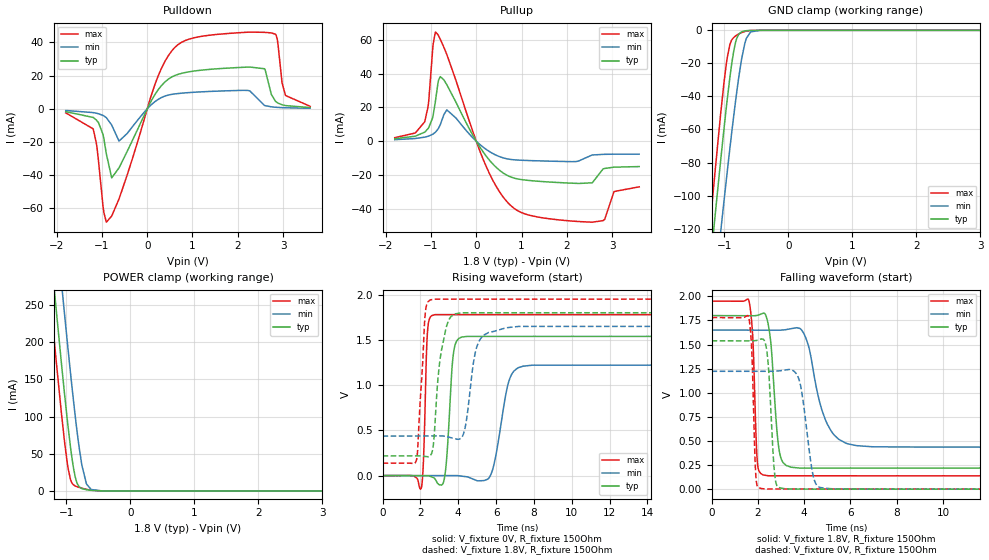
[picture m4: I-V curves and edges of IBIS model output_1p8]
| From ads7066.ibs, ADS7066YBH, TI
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|   output_1p8 Model
[Model]   output_1p8
Model_type   3-state
Polarity   Non-Inverting
Vmeas = 0.9
Vref = 0
Cref = 2pF
Rref = 100000
|   typ   min   max
C_comp   1.386pF   1.367pF   1.411pF
| Where Nom  PVT is Nominal Process, 1.8V, 27C
|   Fast PVT is Strong Process,  1.95V, -40C
|   Slow PVT is Weak Process,   1.65V, 125C
[Voltage Range]   1.8   1.65   1.95
|Junction Temperature
[Temperature Range]   27   125   -40
[Pullup Reference]   1.8   1.65   1.95
[Pulldown Reference]   0   0   0
[Power Clamp Reference]   1.8   1.65   1.95
[GND Clamp Reference]   0   0   0
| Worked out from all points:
|   slope of the pulldown table from 0 to 0.27 V, typ, clamps not added: 21.6 ohm
|   slope of the pullup table from 0 to 0.27 V, typ, clamps not added: 25.7 ohm
|   GND clamp passes 1 mA (typ) near -0.73 V on its own axis
|   POWER clamp passes 1 mA (typ) near -0.63 V on its own axis
|   falling waveform, V_fixture 1.8V, R_fixture 150Ohm: 20-80 % time 278ps typ, 730ps min, 153ps max; typ from 1.8 V to 0.217 V
|   rising waveform, V_fixture 0V, R_fixture 150Ohm: 20-80 % time 258ps typ, 586ps min, 139ps max; typ from 0 V to 1.54 V
|   rising waveform, V_fixture 1.8V, R_fixture 150Ohm: 20-80 % time 454ps typ, 482ps min, 288ps max; typ from 0.217 V to 1.8 V
|   falling waveform, V_fixture 0V, R_fixture 150Ohm: 20-80 % time 208ps typ, 394ps min, 133ps max; typ from 1.54 V to 0 V
[Pulldown]
|   Voltage   I(typ)   I(min)   I(max)
-1.8V     -1.681mA   -997.9uA   -2.413mA
-1.195V   -5.166mA   -2.248mA   -12.05mA
-903.6mV  -27.09mA   -5.271mA   -68.31mA
-784.8mV  -41.57mA   -9.762mA   -64.6mA
-622.8mV  -35.57mA   -19.44mA   -54.28mA
235.8mV   11.27mA    5.583mA    19.38mA
765mV     21.42mA    9.451mA    40.2mA
2.25V     25.18mA    10.95mA    46.24mA
2.59V     24.17mA    2.048mA    46.11mA
2.833V    4.589mA    969.2uA    44.98mA
3.055V    1.954mA    642.4uA    8.054mA
3.6V      774.7uA    346.3uA    1.516mA
[GND Clamp]
|   Voltage   I(typ)   I(min)   I(max)
-1.8V     -380.5mA   -404.1mA   -374.3mA
-1.211V   -138.4mA   -178.5mA   -113.2mA
-1.157V   -117mA     -158.4mA   -90.48mA
-1.06V    -79.58mA   -122.8mA   -51.35mA
-957.6mV  -42.61mA   -86.38mA   -17.06mA
-914.4mV  -28.66mA   -71.59mA   -8.683mA
-849.6mV  -11.69mA   -50.38mA   -4.165mA
-806.4mV  -4.835mA   -37.2mA    -2.914mA
-730.8mV  -904.9uA   -17.35mA   -1.369mA
-655.2mV  -218.7uA   -4.797mA   -452.8uA
-444.6mV  -2.079uA   -17.08uA   -2.822uA
3.6V      0A         0A         0A
[Pullup]
|   Voltage   I(typ)   I(min)   I(max)
-1.8V     1.44mA     905.6uA    2.085mA
-1.141V   5.329mA    2.38mA     11.37mA
-1.055V   7.814mA    2.998mA    22.5mA
-898.2mV  24.36mA    5.408mA    64.56mA
-833.4mV  36.07mA    7.654mA    62.45mA
-714.6mV  36.27mA    15.77mA    55.53mA
235.8mV   -9.388mA   -5.154mA   -15.89mA
840.6mV   -21.86mA   -11.02mA   -39.81mA
2.558V    -24.64mA   -8.187mA   -47.92mA
2.801V    -16.46mA   -7.795mA   -46.99mA
3.044V    -15.36mA   -7.69mA    -29.79mA
3.6V      -15.02mA   -7.65mA    -27.01mA
[POWER Clamp]
|   Voltage   I(typ)   I(min)   I(max)
-1.8V     853mA      961.6mA    785.6mA
-1.433V   499.7mA    610.1mA    430.7mA
-1.222V   302.3mA    412.9mA    232.9mA
-1.19V    272.6mA    383.1mA    203.3mA
-1.076V   171.5mA    280.5mA    104.3mA
-1.028V   130.3mA    237.6mA    66.07mA
-936mV    59.76mA    159.6mA    15.64mA
-860.4mV  18.67mA    100.2mA    6.621mA
-757.8mV  3.121mA    34.87mA    3.656mA
-687.6mV  1.631mA    10.08mA    2.173mA
-612mV    767.1uA    1.938mA    987.9uA
3.6V      0A         0A         0A
[Ramp]
R_load = 150
|   typ   min   max
dV/dt_r   0.923129/2.5797e-10   0.733293/5.85572e-10   1.06765/1.3916e-10
dV/dt_f   0.949699/2.77628e-10   0.728339/7.29494e-10   1.08777/1.52772e-10
[Falling Waveform]
V_fixture = 1.8V
V_fixture_min = 1.65V
V_fixture_max = 1.95V
R_fixture = 150Ohm
C_fixture = 0F
|   Time   V(typ)   V(min)   V(max)
0s        1.8V       1.65V      1.95V
1.617ns   1.799V     1.649V     1.95V
1.786ns   1.798V     1.649V     1.549V
1.987ns   1.803V     1.649V     260mV
2.467ns   1.682V     1.649V     138.6mV
2.959ns   355.6mV    1.649V     138.6mV
3.773ns   219.4mV    1.669V     138.6mV
5.158ns   219.4mV    606.2mV    138.6mV
6.947ns   219.4mV    439.8mV    138.6mV
150ns     217.2mV    436.1mV    137.1mV
[Rising Waveform]
V_fixture = 0V
V_fixture_min = 0V
V_fixture_max = 0V
R_fixture = 150Ohm
C_fixture = 0F
|   Time   V(typ)   V(min)   V(max)
0s        -34.74nV   -25.52nV   -37.16nV
2.044ns   -1.471mV   101.4uV    -140.3mV
2.372ns   -1.708mV   117.7uV    1.58V
2.777ns   -38.29mV   137.8uV    1.778V
3.294ns   -2.091mV   163.5uV    1.778V
3.804ns   1.418V     188.8uV    1.778V
4.468ns   1.538V     -13.76mV   1.778V
5.671ns   1.538V     -11.78mV   1.778V
7.939ns   1.538V     1.22V      1.778V
150ns     1.539V     1.222V     1.779V
[Rising Waveform]
V_fixture = 1.8V
V_fixture_min = 1.65V
V_fixture_max = 1.95V
R_fixture = 150Ohm
C_fixture = 0F
|   Time   V(typ)   V(min)   V(max)
0s        217.2mV    436.1mV    137.1mV
1.786ns   217.9mV    437.3mV    166.2mV
2.262ns   211.2mV    437.6mV    1.8V
2.721ns   418.3mV    437.9mV    1.949V
2.986ns   1.192V     438mV      1.949V
3.33ns    1.603V     433.5mV    1.949V
4.179ns   1.799V     420.2mV    1.949V
5.102ns   1.799V     1.484V     1.949V
7.199ns   1.799V     1.648V     1.949V
150ns     1.8V       1.65V      1.95V
[Falling Waveform]
|Gnd
V_fixture = 0V
V_fixture_min = 0V
V_fixture_max = 0V
R_fixture = 150Ohm
C_fixture = 0F
|   Time   V(typ)   V(min)   V(max)
0s        1.539V     1.222V     1.779V
1.598ns   1.538V     1.222V     1.787V
1.93ns    1.542V     1.222V     91.9mV
2.324ns   1.512V     1.222V     1.338mV
2.771ns   78.1mV     1.224V     1.334mV
3.33ns    1.933mV    1.241V     1.329mV
3.816ns   1.19mV     1.105V     1.324mV
4.447ns   225.4uV    88.6mV     1.319mV
5.3ns     1.742uV    2.901mV    1.311mV
150ns     -34.46nV   -24.41nV   -28.39nV
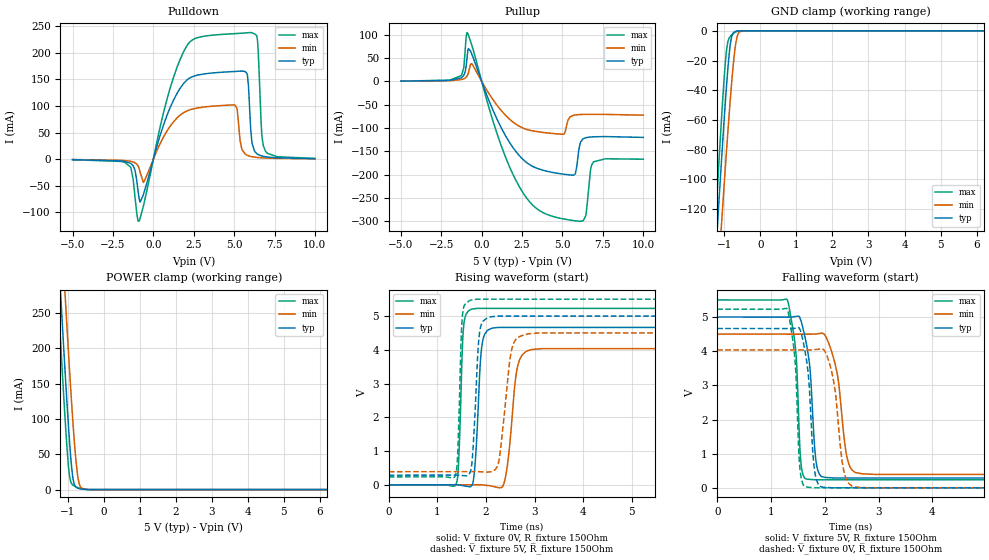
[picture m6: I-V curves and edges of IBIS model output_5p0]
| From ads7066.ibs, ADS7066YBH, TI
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|   output_5p0 Model
[Model]   output_5p0
Model_type   3-state
Polarity   Non-Inverting
Vmeas = 2.5
Vref = 0
Cref = 2pF
Rref = 100000
|   typ   min   max
C_comp   1.190pF   1.174pF   1.207pF
| Where Nom  PVT is Nominal Process, 5.0V, 27C
|   Fast PVT is Strong Process,  5.5V, -40C
|   Slow PVT is Weak Process,   4.5V, 125C
[Voltage Range]   5   4.5   5.5
|Junction Temperature
[Temperature Range]   27   125   -40
[Pullup Reference]   5   4.5   5.5
[Pulldown Reference]   0   0   0
[Power Clamp Reference]   5   4.5   5.5
[GND Clamp Reference]   0   0   0
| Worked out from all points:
|   slope of the pulldown table from 0 to 0.75 V, typ, clamps not added: 10.1 ohm
|   slope of the pullup table from 0 to 0.75 V, typ, clamps not added: 11.4 ohm
|   GND clamp passes 1 mA (typ) near -0.74 V on its own axis
|   POWER clamp passes 1 mA (typ) near -0.64 V on its own axis
|   falling waveform, V_fixture 5V, R_fixture 150Ohm: 20-80 % time 133ps typ, 196ps min, 106ps max; typ from 5 V to 0.286 V
|   rising waveform, V_fixture 0V, R_fixture 150Ohm: 20-80 % time 98ps typ, 157ps min, 69.5ps max; typ from 0 V to 4.66 V
|   rising waveform, V_fixture 5V, R_fixture 150Ohm: 20-80 % time 98.7ps typ, 176ps min, 64.8ps max; typ from 0.286 V to 5 V
|   falling waveform, V_fixture 0V, R_fixture 150Ohm: 20-80 % time 122ps typ, 168ps min, 99.9ps max; typ from 4.66 V to 0 V
[Pulldown]
|   Voltage   I(typ)   I(min)   I(max)
-5V       -802.8uA   -602.9uA   -924.7uA
-1.4V     -7.864mA   -4.004mA   -15.1mA
-875mV    -74.53mA   -17.91mA   -116.1mA
850mV     82.8mA     53.32mA    113.3mA
2.11V     149.8mA    91.26mA    214.9mA
5.05V     165mA      101.8mA    236.1mA
5.695V    164.7mA    9.509mA    237.4mA
6.025V    56.88mA    5.197mA    238.1mA
6.445V    9.659mA    3.261mA    224.1mA
6.715V    6.123mA    2.626mA    46.04mA
6.94V     4.679mA    2.257mA    15.17mA
10V       1.097mA    770.5uA    1.454mA
[GND Clamp]
|   Voltage   I(typ)   I(min)   I(max)
-5V       -1.742A    -1.673A    -1.842A
-1.25V    -153.8mA   -193mA     -129.8mA
-1.145V   -112.2mA   -153.8mA   -85.33mA
-1.1V     -94.73mA   -137.3mA   -66.98mA
-1.055V   -77.63mA   -120.9mA   -49.36mA
-950mV    -40.06mA   -83.75mA   -15.21mA
-905mV    -25.85mA   -68.44mA   -7.567mA
-830mV    -8.054mA   -44.28mA   -3.543mA
-695mV    -458uA     -10.25mA   -854.9uA
-620mV    -110.5uA   -2.108mA   -232.4uA
-485mV    -5.672uA   -52.41uA   -9.063uA
10V       0A         0A         0A
[Pullup]
|   Voltage   I(typ)   I(min)   I(max)
-5V       634.1uA    485uA      702.9uA
-1.25V    7.8mA      4.121mA    12.78mA
-890mV    56.89mA    12.77mA    104.6mA
-605mV    57.91mA    37.69mA    76.91mA
1.765V    -133.2mA   -82.2mA    -186.6mA
2.95V     -178.3mA   -104.6mA   -257.6mA
4.21V     -194mA     -111mA     -287.6mA
5.095V    -199.2mA   -112.7mA   -295.4mA
5.8V      -197.9mA   -71.89mA   -299.1mA
6.295V    -122.9mA   -70.76mA   -298.5mA
6.925V    -118.8mA   -70.58mA   -172.5mA
10V       -120.1mA   -72.34mA   -166.8mA
[POWER Clamp]
|   Voltage   I(typ)   I(min)   I(max)
-5V       4.013A     4.112A     3.953A
-1.43V    497.1mA    607.4mA    428mA
-1.25V    328mA      438.7mA    258.5mA
-1.16V    245.6mA    355.9mA    176.5mA
-1.085V   179mA      288.2mA    111.5mA
-1.04V    140.4mA    248.3mA    75.26mA
-965mV    80.52mA    183.8mA    26.64mA
-845mV    13.67mA    88.99mA    6.045mA
-710mV    1.982mA    15.78mA    2.609mA
-620mV    840.5uA    2.3mA      1.091mA
-440mV    37.51uA    71.19uA    30.49uA
10V       0A         0A         0A
[Ramp]
R_load = 150
|   typ   min   max
dV/dt_r   2.79865/9.80149e-11   2.42204/1.56934e-10   3.13678/6.94831e-11
dV/dt_f   2.8283/1.33472e-10   2.4666/1.96375e-10   3.1587/1.05529e-10
[Falling Waveform]
V_fixture = 5V
V_fixture_min = 4.5V
V_fixture_max = 5.5V
R_fixture = 150Ohm
C_fixture = 0F
|   Time   V(typ)   V(min)   V(max)
0s        5V         4.5V       5.5V
1.305ns   4.998V     4.499V     5.496V
1.461ns   5.017V     4.498V     3.993V
1.571ns   4.819V     4.498V     554.7mV
1.72ns    3.56V      4.498V     248mV
1.809ns   1.235V     4.502V     237.4mV
2.172ns   289.5mV    3.746V     237.4mV
2.468ns   288.4mV    617.5mV    237.4mV
2.949ns   288.4mV    392.4mV    237.4mV
150ns     286.2mV    389mV      235.5mV
[Rising Waveform]
V_fixture = 0V
V_fixture_min = 0V
V_fixture_max = 0V
R_fixture = 150Ohm
C_fixture = 0F
|   Time   V(typ)   V(min)   V(max)
0s        -80.46nV   18.06nV    -27.53nV
1.383ns   2.54mV     1.917mV    13.55mV
1.547ns   -29mV      2.143mV    4.802V
1.728ns   51.32mV    2.395mV    5.209V
1.809ns   1.411V     2.507mV    5.226V
1.973ns   4.463V     -9.761mV   5.226V
2.353ns   4.662V     -16.44mV   5.226V
2.659ns   4.662V     3.566V     5.226V
3.153ns   4.662V     4.034V     5.226V
150ns     4.664V     4.037V     5.228V
[Rising Waveform]
V_fixture = 5V
V_fixture_min = 4.5V
V_fixture_max = 5.5V
R_fixture = 150Ohm
C_fixture = 0F
|   Time   V(typ)   V(min)   V(max)
0s        286.2mV    389mV      235.5mV
1.362ns   288.7mV    390.3mV    255.4mV
1.521ns   274.8mV    390.5mV    5.102V
1.7ns     533.2mV    390.6mV    5.474V
1.809ns   3.254V     390.7mV    5.498V
1.946ns   4.857V     383.2mV    5.498V
2.261ns   4.999V     695.2mV    5.498V
2.565ns   4.999V     4.186V     5.498V
3.092ns   4.999V     4.498V     5.498V
150ns     5V         4.5V       5.5V
[Falling Waveform]
|Gnd
V_fixture = 0V
V_fixture_min = 0V
V_fixture_max = 0V
R_fixture = 150Ohm
C_fixture = 0F
|   Time   V(typ)   V(min)   V(max)
0s        4.664V     4.037V     5.228V
1.298ns   4.663V     4.036V     5.245V
1.444ns   4.669V     4.036V     3.794V
1.555ns   4.564V     4.036V     352.5mV
1.7ns     3.194V     4.036V     18.83mV
1.782ns   954.9mV    4.04V      2.091mV
2.106ns   4.763mV    3.541V     2.086mV
2.388ns   2.361mV    303.9mV    2.082mV
2.794ns   2.355mV    3.691mV    2.077mV
150ns     -75.35nV   -50.19nV   -28.34nV
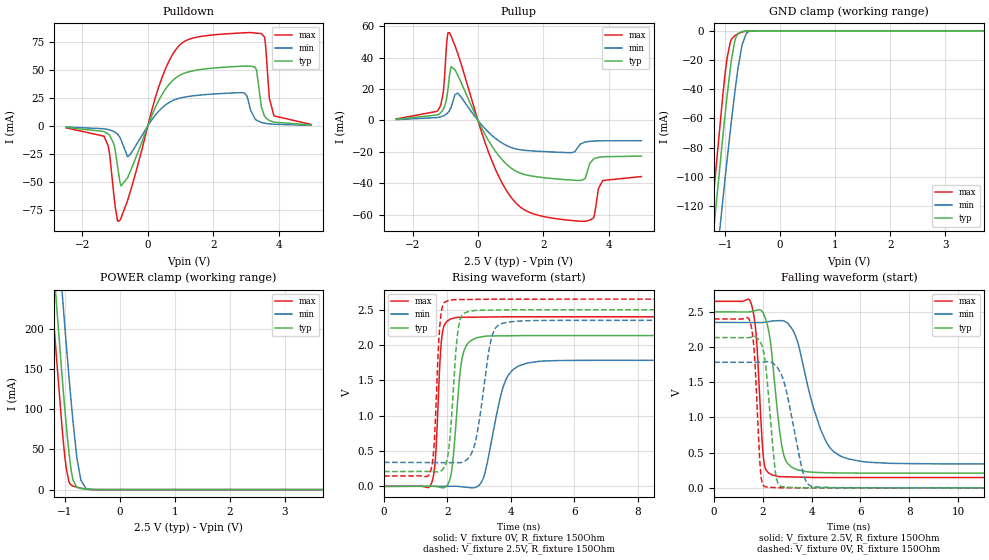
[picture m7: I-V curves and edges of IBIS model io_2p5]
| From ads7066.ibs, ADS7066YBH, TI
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|   io_2p5 Model
[Model]   io_2p5
Model_type   I/O
Polarity   Non-Inverting
Enable   Active-Low
Vinl = 0.75
Vinh = 1.75
Vmeas = 1.25
Vref = 0
Cref = 2pF
Rref = 100000
|   typ   min   max
C_comp   1.258pF   1.229pF   1.287pF
[Model spec]
|subparameter
Vinl   0.75   0.705   0.795
Vinh   1.75   1.645   1.855
| Where Nom  PVT is Nominal Process, 2.5V, 27C
|   Fast PVT is Strong Process,  2.65V, -40C
|   Slow PVT is Weak Process,   2.35V, 125C
[Voltage Range]   2.5   2.35   2.65
|Junction Temperature
[Temperature Range]   27   125   -40
[Pullup Reference]   2.5   2.35   2.65
[Pulldown Reference]   0   0   0
[Power Clamp Reference]   2.5   2.35   2.65
[GND Clamp Reference]   0   0   0
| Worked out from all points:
|   slope of the pulldown table from 0 to 0.375 V, typ, clamps not added: 15 ohm
|   slope of the pullup table from 0 to 0.375 V, typ, clamps not added: 25.8 ohm
|   GND clamp passes 1 mA (typ) near -0.72 V on its own axis
|   POWER clamp passes 1 mA (typ) near -0.67 V on its own axis
|   falling waveform, V_fixture 2.5V, R_fixture 150Ohm: 20-80 % time 423ps typ, 960ps min, 242ps max; typ from 2.5 V to 0.21 V
|   rising waveform, V_fixture 0V, R_fixture 150Ohm: 20-80 % time 240ps typ, 505ps min, 152ps max; typ from 0 V to 2.13 V
|   rising waveform, V_fixture 2.5V, R_fixture 150Ohm: 20-80 % time 218ps typ, 385ps min, 152ps max; typ from 0.21 V to 2.5 V
|   falling waveform, V_fixture 0V, R_fixture 150Ohm: 20-80 % time 325ps typ, 626ps min, 208ps max; typ from 2.13 V to 0 V
[Pulldown]
|   Voltage   I(typ)   I(min)   I(max)
-2.5V     -1.292mA   -871.2uA   -1.667mA
-1.337V   -5.027mA   -2.545mA   -9.381mA
-917.5mV  -37.74mA   -7.576mA   -85.4mA
-617.5mV  -46.32mA   -27.69mA   -66.67mA
440mV     28.4mA     16.34mA    43.78mA
1.175V    47.83mA    26.11mA    76.61mA
2.96V     53.64mA    29.38mA    83.48mA
3.283V    52.72mA    6.203mA    83.32mA
3.478V    16.66mA    3.106mA    82.67mA
3.583V    8.438mA    2.416mA    77.51mA
3.86V     3.367mA    1.506mA    9.07mA
5V        924.1uA    578.8uA    1.32mA
[GND Clamp]
|   Voltage   I(typ)   I(min)   I(max)
-2.5V     -675.9mA   -679.1mA   -693mA
-1.27V    -162mA     -200.6mA   -138.5mA
-1.195V   -132mA     -172.5mA   -106.4mA
-1.038V   -71.16mA   -114.7mA   -42.87mA
-962.5mV  -44.32mA   -88.16mA   -18.39mA
-902.5mV  -25.15mA   -67.67mA   -7.363mA
-827.5mV  -7.684mA   -43.57mA   -3.512mA
-775mV    -2.361mA   -28.38mA   -2.225mA
-692.5mV  -445.3uA   -9.862mA   -836.9uA
-617.5mV  -107.3uA   -2.001mA   -224.7uA
-490mV    -6.538uA   -62.46uA   -10.58uA
5V        0A         0A         0A
[Pullup]
|   Voltage   I(typ)   I(min)   I(max)
-2.5V     749.8uA    515.3uA    949.2uA
-1.173V   4.383mA    2.136mA    8.127mA
-1.067V   6.804mA    2.809mA    16.96mA
-955mV    14.24mA    4.158mA    49.66mA
-872.5mV  28.11mA    6.155mA    55.9mA
-617.5mV  28.8mA     17.38mA    42.61mA
440mV     -16.69mA   -9.746mA   -26.38mA
1.302V    -33.58mA   -18.68mA   -55.19mA
3.147V    -38.18mA   -14.93mA   -64.15mA
3.425V    -27.2mA    -13.3mA    -63.43mA
3.822V    -23.1mA    -12.95mA   -38.2mA
5V        -22.69mA   -12.92mA   -35.72mA
[POWER Clamp]
|   Voltage   I(typ)   I(min)   I(max)
-2.5V     1.528A     1.631A     1.466A
-1.24V    309.9mA    417.8mA    242.2mA
-1.21V    282.3mA    390.1mA    214.7mA
-1.045V   136.5mA    241.6mA    72.79mA
-977.5mV  82.45mA    183.6mA    27.9mA
-925mV    45.92mA    140.4mA    9.647mA
-887.5mV  25.32mA    111mA      5.743mA
-857.5mV  13.78mA    88.82mA    4.572mA
-775mV    2.712mA    37mA       2.848mA
-707.5mV  1.354mA    11.49mA    1.787mA
-580mV    357uA      701.7uA    441.4uA
5V        0A         0A         0A
[Ramp]
R_load = 150
|   typ   min   max
dV/dt_r   1.28092/2.39622e-10   1.0705/5.04885e-10   1.43961/1.51626e-10
dV/dt_f   1.3743/4.22149e-10   1.20633/9.55966e-10   1.50213/2.41037e-10
[Falling Waveform]
V_fixture = 2.5V
V_fixture_min = 2.35V
V_fixture_max = 2.65V
R_fixture = 150Ohm
C_fixture = 0F
|   Time   V(typ)   V(min)   V(max)
0s        2.5V       2.35V      2.65V
1.514ns   2.504V     2.349V     2.627V
1.733ns   2.522V     2.349V     2.145V
2.052ns   2.452V     2.352V     351.9mV
2.297ns   2.106V     2.365V     199.5mV
2.61ns    1.047V     2.375V     162.8mV
3.149ns   300.6mV    2.279V     155.5mV
4.603ns   214.1mV    649.2mV    146.6mV
6.045ns   209.8mV    375.3mV    146.6mV
50ns      209.5mV    339.4mV    146.4mV
[Rising Waveform]
V_fixture = 0V
V_fixture_min = 0V
V_fixture_max = 0V
R_fixture = 150Ohm
C_fixture = 0F
|   Time   V(typ)   V(min)   V(max)
0s        -37.71nV   -68.14nV   -70.46nV
1.488ns   1.54mV     1.011mV    31.4mV
1.618ns   -1.517mV   1.099mV    377.1mV
1.845ns   -20.22mV   1.254mV    2.187V
2.123ns   192.9mV    1.443mV    2.372V
2.292ns   1.036V     1.057mV    2.391V
2.708ns   2.054V     -18.69mV   2.394V
3.898ns   2.131V     1.559V     2.399V
4.881ns   2.135V     1.769V     2.399V
50ns      2.135V     1.784V     2.399V
[Rising Waveform]
V_fixture = 2.5V
V_fixture_min = 2.35V
V_fixture_max = 2.65V
R_fixture = 150Ohm
C_fixture = 0F
|   Time   V(typ)   V(min)   V(max)
0s        209.5mV    339.4mV    146.4mV
1.456ns   210.5mV    336.6mV    194.6mV
1.583ns   208.8mV    336.3mV    615.7mV
1.796ns   219.5mV    335.9mV    2.433V
2.169ns   1.254V     335.2mV    2.642V
2.439ns   2.41V      337.6mV    2.644V
2.868ns   2.49V      609.3mV    2.646V
3.438ns   2.495V     2.172V     2.649V
4.125ns   2.5V       2.336V     2.65V
50ns      2.5V       2.35V      2.65V
[Falling Waveform]
|Gnd
V_fixture = 0V
V_fixture_min = 0V
V_fixture_max = 0V
R_fixture = 150Ohm
C_fixture = 0F
|   Time   V(typ)   V(min)   V(max)
0s        2.135V     1.784V     2.399V
1.47ns    2.137V     1.784V     2.368V
1.648ns   2.149V     1.783V     1.931V
1.92ns    2.056V     1.783V     179.8mV
2.19ns    1.47V      1.793V     10.41mV
2.463ns   379.1mV    1.756V     5.006mV
2.611ns   72.27mV    1.7V       2.701mV
3.681ns   1.941mV    173.5mV    278.1uV
4.125ns   1.327mV    14.44mV    146.3uV
50ns      -12.98nV   -31.25nV   -63.6nV
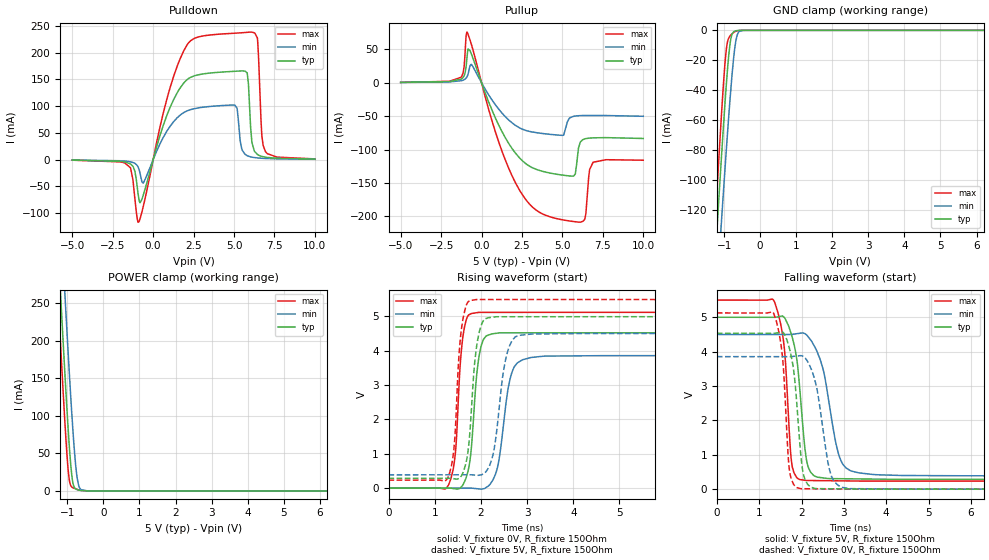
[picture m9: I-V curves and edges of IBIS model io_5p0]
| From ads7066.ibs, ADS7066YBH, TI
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|   io_5p0 Model
[Model]   io_5p0
Model_type   I/O
Polarity   Non-Inverting
Enable   Active-Low
Vinl = 1.5
Vinh = 3.5
Vmeas = 2.5
Vref = 0
Cref = 2pF
Rref = 100000
|   typ   min   max
C_comp   1.126pF   1.111pF   1.147pF
[Model spec]
|subparameter
Vinl   1.5   1.35   1.65
Vinh   3.5   3.15   3.85
| Where Nom  PVT is Nominal Process, 5.0V, 27C
|   Fast PVT is Strong Process,  5.5V, -40C
|   Slow PVT is Weak Process,   4.5V, 125C
[Voltage Range]   5   4.5   5.5
|Junction Temperature
[Temperature Range]   27   125   -40
[Pullup Reference]   5   4.5   5.5
[Pulldown Reference]   0   0   0
[Power Clamp Reference]   5   4.5   5.5
[GND Clamp Reference]   0   0   0
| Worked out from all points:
|   slope of the pulldown table from 0 to 0.75 V, typ, clamps not added: 10.1 ohm
|   slope of the pullup table from 0 to 0.75 V, typ, clamps not added: 16.1 ohm
|   GND clamp passes 1 mA (typ) near -0.73 V on its own axis
|   POWER clamp passes 1 mA (typ) near -0.67 V on its own axis
|   falling waveform, V_fixture 5V, R_fixture 150Ohm: 20-80 % time 227ps typ, 372ps min, 171ps max; typ from 5 V to 0.286 V
|   rising waveform, V_fixture 0V, R_fixture 150Ohm: 20-80 % time 165ps typ, 234ps min, 138ps max; typ from 0 V to 4.54 V
|   rising waveform, V_fixture 5V, R_fixture 150Ohm: 20-80 % time 166ps typ, 230ps min, 137ps max; typ from 0.286 V to 5 V
|   falling waveform, V_fixture 0V, R_fixture 150Ohm: 20-80 % time 197ps typ, 293ps min, 155ps max; typ from 4.54 V to 0 V
[Pulldown]
|   Voltage   I(typ)   I(min)   I(max)
-5V       -802.8uA   -602.9uA   -924.7uA
-1.4V     -7.866mA   -4.004mA   -15.11mA
-875mV    -74.51mA   -17.91mA   -116.1mA
2.11V     149.8mA    91.26mA    214.9mA
5.05V     165mA      102mA      236.1mA
5.695V    165.2mA    9.798mA    237.4mA
5.89V     141.8mA    6.531mA    237.9mA
6.025V    61.06mA    5.286mA    238.2mA
6.445V    9.826mA    3.297mA    227.4mA
6.715V    6.19mA     2.649mA    47.98mA
6.94V     4.718mA    2.274mA    15.37mA
10V       1.1mA      772.6uA    1.456mA
[GND Clamp]
|   Voltage   I(typ)   I(min)   I(max)
-5V       -1.743A    -1.673A    -1.842A
-1.25V    -153.9mA   -193.1mA   -129.9mA
-1.145V   -112.3mA   -153.9mA   -85.4mA
-1.1V     -94.8mA    -137.4mA   -67.04mA
-1.055V   -77.69mA   -121mA     -49.42mA
-950mV    -40.1mA    -83.82mA   -15.26mA
-905mV    -25.89mA   -68.5mA    -7.622mA
-830mV    -8.086mA   -44.33mA   -3.584mA
-695mV    -466.3uA   -10.28mA   -867.7uA
-620mV    -112.8uA   -2.129mA   -236.4uA
-485mV    -5.784uA   -54.34uA   -9.217uA
10V       0A         0A         0A
[Pullup]
|   Voltage   I(typ)   I(min)   I(max)
-5V       442.6uA    340.9uA    488.1uA
-1.25V    5.358mA    2.923mA    8.28mA
-890mV    39.65mA    9.216mA    75.45mA
-620mV    42.36mA    27.21mA    56.72mA
1.705V    -91.7mA    -56.29mA   -129.3mA
4.21V     -135mA     -77.15mA   -200.3mA
5.695V    -139.7mA   -50.25mA   -207.5mA
6.1V      -89.28mA   -49.25mA   -208.5mA
6.385V    -84.03mA   -49.05mA   -204.1mA
6.685V    -82.79mA   -48.98mA   -129.8mA
6.91V     -82.43mA   -48.98mA   -118.9mA
10V       -83.38mA   -50.22mA   -115.9mA
[POWER Clamp]
|   Voltage   I(typ)   I(min)   I(max)
-5V       4.003A     4.099A     3.946A
-1.43V    488mA      595.5mA    420.9mA
-1.25V    319.1mA    427mA      251.4mA
-1.16V    236.9mA    344.4mA    169.6mA
-1.07V    157.6mA    263.6mA    92.54mA
-965mV    73.17mA    173.2mA    21.87mA
-920mV    42.85mA    136.4mA    8.823mA
-860mV    14.55mA    90.62mA    4.645mA
-740mV    1.818mA    21.42mA    2.271mA
-635mV    689uA      2.264mA    905.9uA
-440mV    26.07uA    49.48uA    21.19uA
10V       0A         0A         0A
[Ramp]
R_load = 150
|   typ   min   max
dV/dt_r   2.72071/1.64667e-10   2.31301/2.3211e-10   3.07527/1.36544e-10
dV/dt_f   2.8283/2.26559e-10   2.4666/3.6878e-10   3.1587/1.71031e-10
[Falling Waveform]
V_fixture = 5V
V_fixture_min = 4.5V
V_fixture_max = 5.5V
R_fixture = 150Ohm
C_fixture = 0F
|   Time   V(typ)   V(min)   V(max)
0s        5V         4.5V       5.5V
1.353ns   4.999V     4.499V     5.466V
1.593ns   4.993V     4.499V     4.103V
1.774ns   4.446V     4.502V     702mV
1.909ns   3.571V     4.525V     313.7mV
2.094ns   1.047V     4.51V      255.2mV
2.503ns   328.8mV    3.52V      247.4mV
2.944ns   303.6mV    796.5mV    241.6mV
3.69ns    293.4mV    426.9mV    235.8mV
50ns      286.2mV    389mV      235.5mV
[Rising Waveform]
V_fixture = 0V
V_fixture_min = 0V
V_fixture_max = 0V
R_fixture = 150Ohm
C_fixture = 0F
|   Time   V(typ)   V(min)   V(max)
0s        -63.66nV   -73.22nV   -60.98nV
1.295ns   1.769mV    1.613mV    85.51mV
1.429ns   -14.95mV   1.779mV    799.8mV
1.568ns   29.96mV    1.953mV    3.868V
1.718ns   478.2mV    2.14mV     5.009V
1.95ns    3.753V     -19.31mV   5.113V
2.335ns   4.505V     487.5mV    5.113V
2.711ns   4.519V     3.499V     5.113V
3.349ns   4.519V     3.838V     5.113V
50ns      4.535V     3.855V     5.125V
[Rising Waveform]
V_fixture = 5V
V_fixture_min = 4.5V
V_fixture_max = 5.5V
R_fixture = 150Ohm
C_fixture = 0F
|   Time   V(typ)   V(min)   V(max)
0s        286.2mV    389mV      235.5mV
1.282ns   287.9mV    390.4mV    302.1mV
1.415ns   276.1mV    390.5mV    1.136V
1.535ns   294.1mV    390.6mV    4.041V
1.675ns   718mV      390.8mV    5.286V
1.901ns   4.062V     379.8mV    5.486V
2.235ns   4.97V      831.5mV    5.486V
2.62ns    4.986V     4.138V     5.486V
3.086ns   4.986V     4.482V     5.486V
50ns      5V         4.5V       5.5V
[Falling Waveform]
|Gnd
V_fixture = 0V
V_fixture_min = 0V
V_fixture_max = 0V
R_fixture = 150Ohm
C_fixture = 0F
|   Time   V(typ)   V(min)   V(max)
0s        4.535V     3.855V     5.125V
1.344ns   4.533V     3.854V     5.11V
1.544ns   4.57V      3.854V     3.909V
1.738ns   3.976V     3.854V     388.4mV
1.976ns   1.089V     3.884V     14.63mV
2.087ns   263.1mV    3.814V     12.6mV
2.311ns   24.46mV    3.192V     10.27mV
2.695ns   11.83mV    416.9mV    6.264mV
3.123ns   7.374mV    16.77mV    1.812mV
50ns      -117.8nV   -45.16nV   -71.52nV
